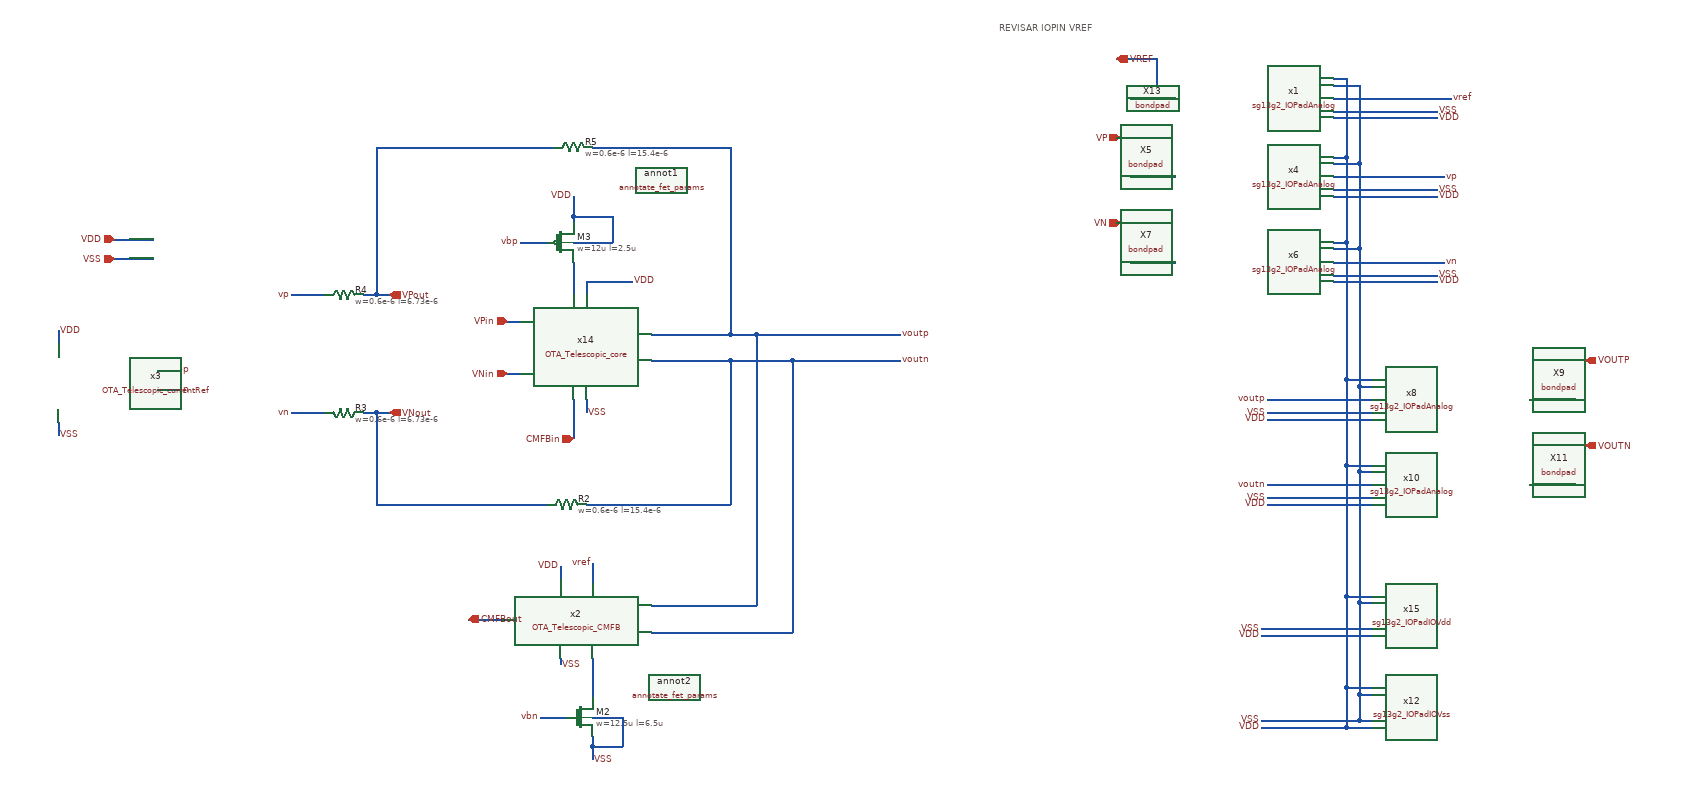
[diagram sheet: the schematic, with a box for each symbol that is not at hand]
v {xschem version=3.4.8RC file_version=1.3}
G {}
K {}
V {}
S {}
F {}
E {}
T {REVISAR IOPIN VREF} 1730 -1240 0 0 0.4 0.4 {}
N 1100 -660 1100 -640 {lab=VSS}
N 1080 -660 1080 -600 {lab=CMFBin}
N 1060 -265 1060 -255 {lab=VSS}
N 920 -325 970 -325 {lab=CMFBout}
N 1110 -1045 1320 -1045 {lab=voutp}
N 780 -640 780 -500 {lab=VNout}
N 1100 -500 1320 -500 {lab=voutp}
N 1320 -720 1320 -500 {lab=voutp}
N 1200 -305 1415 -305 {lab=voutp}
N 1200 -345 1360 -345 {lab=voutp}
N 1060 -405 1060 -385 {lab=VDD}
N 1110 -265 1110 -205 {lab=#net1}
N 780 -640 800 -640 {lab=VNout}
N 780 -820 800 -820 {lab=VPout}
N 1030 -175 1070 -175 {
lab=vbn}
N 1110 -175 1155 -175 {lab=VSS}
N 1155 -175 1155 -130 {lab=VSS}
N 1110 -130 1155 -130 {lab=VSS}
N 1110 -145 1110 -130 {lab=VSS}
N 1110 -130 1110 -110 {lab=VSS}
N 1080 -940 1080 -930 {lab=VDD}
N 1080 -900 1140 -900 {lab=VDD}
N 1140 -940 1140 -900 {lab=VDD}
N 1080 -940 1140 -940 {lab=VDD}
N 1080 -970 1080 -940 {lab=VDD}
N 445 -675 465 -675 {lab=vbn}
N 980 -700 1000 -700 {lab=VNin}
N 980 -780 1000 -780 {lab=VPin}
N 445 -705 465 -705 {lab=vbp}
N 1000 -900 1040 -900 {
lab=vbp}
N 780 -1045 780 -820 {lab=VPout}
N 1320 -1045 1320 -760 {lab=voutp}
N 1100 -840 1100 -820 {lab=VDD}
N 1100 -840 1170 -840 {lab=VDD}
N 1080 -870 1080 -820 {lab=#net2}
N 760 -640 780 -640 {lab=VNout}
N 780 -500 1040 -500 {lab=VNout}
N 760 -820 780 -820 {lab=VPout}
N 780 -1045 1050 -1045 {lab=VPout}
N 1200 -760 1320 -760 {lab=voutp}
N 1200 -720 1320 -720 {lab=voutp}
N 380 -905 440 -905 {lab=VDD}
N 380 -875 440 -875 {lab=VSS}
N 1360 -760 1360 -345 {lab=voutp}
N 1320 -760 1360 -760 {lab=voutp}
N 1415 -720 1415 -305 {lab=voutp}
N 295 -765 295 -745 {lab=VDD}
N 295 -625 295 -605 {lab=VSS}
N 1970 -1000 2000 -1000 {
lab=VP}
N 1910 -1060 1970 -1060 {
lab=VP}
N 1970 -1060 1970 -1000 {
lab=VP}
N 1930 -1000 1970 -1000 {
lab=VP}
N 650 -820 700 -820 {
lab=vp}
N 2240 -1000 2410 -1000 {
lab=vp}
N 1970 -870 2000 -870 {
lab=VN}
N 1910 -930 1970 -930 {
lab=VN}
N 1970 -930 1970 -870 {
lab=VN}
N 1930 -870 1970 -870 {
lab=VN}
N 2240 -870 2410 -870 {
lab=vn}
N 650 -640 700 -640 {
lab=vn}
N 2540 -660 2570 -660 {
lab=VOUTP}
N 2570 -720 2630 -720 {
lab=VOUTP}
N 2570 -720 2570 -660 {
lab=VOUTP}
N 2570 -660 2610 -660 {
lab=VOUTP}
N 2140 -660 2300 -660 {
lab=voutp}
N 2540 -530 2570 -530 {
lab=VOUTN}
N 2570 -590 2630 -590 {
lab=VOUTN}
N 2570 -590 2570 -530 {
lab=VOUTN}
N 2570 -530 2610 -530 {
lab=VOUTN}
N 2140 -530 2300 -530 {
lab=voutn}
N 1415 -720 1580 -720 {
lab=voutp}
N 1320 -720 1415 -720 {lab=voutp}
N 1360 -760 1580 -760 {
lab=voutp}
N 1970 -1120 2000 -1120 {
lab=VREF}
N 1910 -1180 1970 -1180 {
lab=VREF}
N 1970 -1180 1970 -1120 {
lab=VREF}
N 1930 -1120 1970 -1120 {
lab=VREF}
N 2240 -1120 2420 -1120 {
lab=vref}
N 1110 -410 1110 -380 {
lab=vref}
N 2280 -350 2300 -350 {
lab=VSS}
N 2280 -550 2300 -550 {
lab=VSS}
N 2280 -680 2300 -680 {
lab=VSS}
N 2140 -510 2300 -510 {
lab=VSS}
N 2140 -500 2300 -500 {
lab=VDD}
N 2140 -640 2300 -640 {
lab=VSS}
N 2140 -630 2300 -630 {
lab=VDD}
N 2240 -850 2400 -850 {
lab=VSS}
N 2240 -840 2400 -840 {
lab=VDD}
N 2240 -980 2400 -980 {
lab=VSS}
N 2240 -970 2400 -970 {
lab=VDD}
N 2240 -1100 2400 -1100 {
lab=VSS}
N 2240 -1090 2400 -1090 {
lab=VDD}
N 2240 -890 2280 -890 {
lab=VSS}
N 2240 -900 2260 -900 {
lab=VDD}
N 2240 -1020 2280 -1020 {
lab=VSS}
N 2240 -1030 2260 -1030 {
lab=VDD}
N 2240 -1140 2280 -1140 {
lab=VSS}
N 2240 -1150 2260 -1150 {
lab=VDD}
N 2260 -360 2300 -360 {
lab=VDD}
N 2130 -310 2300 -310 {
lab=VSS}
N 2130 -300 2300 -300 {
lab=VDD}
N 2280 -550 2280 -350 {
lab=VSS}
N 2260 -560 2300 -560 {
lab=VDD}
N 2260 -560 2260 -360 {
lab=VDD}
N 2260 -690 2260 -560 {
lab=VDD}
N 2260 -690 2300 -690 {
lab=VDD}
N 2280 -680 2280 -550 {
lab=VSS}
N 2260 -900 2260 -690 {
lab=VDD}
N 2280 -890 2280 -680 {
lab=VSS}
N 2280 -1020 2280 -890 {
lab=VSS}
N 2280 -1140 2280 -1020 {
lab=VSS}
N 2260 -1030 2260 -900 {
lab=VDD}
N 2260 -1150 2260 -1030 {
lab=VDD}
N 2260 -220 2260 -160 {lab=VDD}
N 2280 -170 2300 -170 {
lab=VSS}
N 2280 -210 2280 -170 {lab=VSS}
N 2260 -160 2300 -160 {
lab=VDD}
N 2130 -160 2260 -160 {
lab=VDD}
N 2130 -170 2280 -170 {
lab=VSS}
N 2280 -210 2300 -210 {lab=VSS}
N 2280 -350 2280 -210 {lab=VSS}
N 2260 -220 2300 -220 {lab=VDD}
N 2260 -360 2260 -220 {lab=VDD}
C {lab_wire.sym} 1170 -840 2 0 {name=p10 sig_type=std_logic lab=VDD}
C {OTA_Telescopic_CMFB.sym} 1120 -325 0 1 {name=x2}
C {sg13g2_pr/sg13_lv_pmos.sym} 1060 -900 0 0 {name=M3
l=2.5u
w=12u
ng=2
m=1
model=sg13_lv_pmos
spiceprefix=X
}
C {lab_wire.sym} 1080 -970 0 0 {name=p15 sig_type=std_logic lab=VDD}
C {lab_wire.sym} 295 -765 0 1 {name=p2 sig_type=std_logic lab=VDD}
C {sg13g2_pr/sg13_lv_nmos.sym} 1090 -175 0 0 {name=M2
l=6.5u
w=12.5u
ng=2
m=1
model=sg13_lv_nmos
spiceprefix=X
}
C {lab_wire.sym} 1030 -175 0 0 {name=p13 sig_type=std_logic lab=vbn}
C {lab_wire.sym} 465 -675 0 1 {name=p16 sig_type=std_logic lab=vbn}
C {lab_wire.sym} 1100 -640 2 0 {name=p1 sig_type=std_logic lab=VSS}
C {lab_wire.sym} 1060 -255 2 0 {name=p4 sig_type=std_logic lab=VSS}
C {lab_wire.sym} 1110 -110 2 0 {name=p17 sig_type=std_logic lab=VSS}
C {lab_wire.sym} 295 -605 2 0 {name=p20 sig_type=std_logic lab=VSS}
C {ipin.sym} 980 -780 0 0 {name=p6 lab=VPin}
C {ipin.sym} 980 -700 0 0 {name=p9 lab=VNin}
C {iopin.sym} 380 -905 2 0 {name=p19 lab=VDD}
C {iopin.sym} 380 -875 2 0 {name=p23 lab=VSS}
C {lab_wire.sym} 465 -705 0 1 {name=p24 sig_type=std_logic lab=vbp}
C {lab_wire.sym} 1000 -900 0 0 {name=p25 sig_type=std_logic lab=vbp}
C {ipin.sym} 1080 -600 0 0 {name=p3 lab=CMFBin}
C {opin.sym} 920 -325 2 0 {name=p14 lab=CMFBout}
C {sg13g2_pr/rppd.sym} 730 -640 1 0 {name=R3
w=0.6e-6
l=6.73e-6
model=rppd
body=VSS
spiceprefix=X
b=0
m=1
}
C {sg13g2_pr/rppd.sym} 730 -820 3 0 {name=R4
w=0.6e-6
l=6.73e-6
model=rppd
body=VSS
spiceprefix=X
b=0
m=1
}
C {sg13g2_pr/rppd.sym} 1080 -1045 3 0 {name=R5
w=0.6e-6
l=15.4e-6
model=rppd
body=VSS
spiceprefix=X
b=0
m=1
}
C {sg13g2_pr/rppd.sym} 1070 -500 3 0 {name=R2
w=0.6e-6
l=15.4e-6
model=rppd
body=VSS
spiceprefix=X
b=0
m=1
}
C {OTA_Telescopic_currentRef.sym} 295 -685 0 0 {name=x3}
C {sg13g2_pr/annotate_fet_params.sym} 1215 -995 0 0 {name=annot1 ref=M3}
C {sg13g2_pr/annotate_fet_params.sym} 1235 -220 0 0 {name=annot2 ref=M2}
C {ipin.sym} 1915 -1060 0 0 {name=p26 lab=VP}
C {sg13g2_pr/bondpad.sym} 1890 -1000 3 0 {name=X5
model=bondpad
spiceprefix=X
size=80u
shape=0
padtype=0
}
C {lab_wire.sym} 650 -820 0 0 {name=p27 sig_type=std_logic lab=vp}
C {lab_wire.sym} 2410 -1000 0 1 {name=p28 sig_type=std_logic lab=vp}
C {ipin.sym} 1915 -930 0 0 {name=p21 lab=VN}
C {sg13g2_pr/bondpad.sym} 1890 -870 3 0 {name=X7
model=bondpad
spiceprefix=X
size=80u
shape=0
padtype=0
}
C {lab_wire.sym} 2410 -870 0 1 {name=p29 sig_type=std_logic lab=vn}
C {lab_wire.sym} 650 -640 0 0 {name=p7 sig_type=std_logic lab=vn}
C {sg13g2_pr/bondpad.sym} 2650 -660 1 1 {name=X9
model=bondpad
spiceprefix=X
size=80u
shape=0
padtype=0
}
C {lab_wire.sym} 2140 -660 0 0 {name=p31 sig_type=std_logic lab=voutp}
C {sg13g2_pr/bondpad.sym} 2650 -530 1 1 {name=X11
model=bondpad
spiceprefix=X
size=80u
shape=0
padtype=0
}
C {opin.sym} 2625 -720 0 0 {name=p8 lab=VOUTP}
C {opin.sym} 2625 -590 0 0 {name=p22 lab=VOUTN}
C {lab_wire.sym} 1580 -720 0 1 {name=p30 sig_type=std_logic lab=voutn}
C {lab_wire.sym} 1580 -760 0 1 {name=p33 sig_type=std_logic lab=voutp}
C {lab_wire.sym} 2140 -530 0 0 {name=p37 sig_type=std_logic lab=voutn}
C {opin.sym} 800 -820 0 0 {name=p12 lab=VPout}
C {opin.sym} 800 -640 0 0 {name=p18 lab=VNout}
C {sg13g2_pr/bondpad.sym} 1890 -1120 3 0 {name=X13
model=bondpad
spiceprefix=X
size=80u
shape=0
padtype=0
}
C {lab_wire.sym} 2420 -1120 0 1 {name=p34 sig_type=std_logic lab=vref}
C {lab_wire.sym} 1110 -410 0 0 {name=p11 sig_type=std_logic lab=vref}
C {lab_wire.sym} 1060 -405 0 0 {name=p5 sig_type=std_logic lab=VDD}
C {OTA_Telescopic_core.sym} 1080 -740 0 0 {name=x14}
C {IOCells/sg13g2_IOPadAnalog.sym} 2120 -1120 0 1 {name=x1}
C {IOCells/sg13g2_IOPadAnalog.sym} 2120 -1000 0 1 {name=x4}
C {IOCells/sg13g2_IOPadAnalog.sym} 2120 -870 0 1 {name=x6}
C {IOCells/sg13g2_IOPadAnalog.sym} 2420 -660 0 0 {name=x8}
C {IOCells/sg13g2_IOPadAnalog.sym} 2420 -530 0 0 {name=x10}
C {lab_wire.sym} 2130 -310 0 0 {name=p42 sig_type=std_logic lab=VSS}
C {lab_wire.sym} 2130 -300 2 1 {name=p43 sig_type=std_logic lab=VDD}
C {lab_wire.sym} 2140 -510 0 0 {name=p48 sig_type=std_logic lab=VSS}
C {lab_wire.sym} 2140 -500 2 1 {name=p49 sig_type=std_logic lab=VDD}
C {lab_wire.sym} 2140 -640 0 0 {name=p50 sig_type=std_logic lab=VSS}
C {lab_wire.sym} 2140 -630 2 1 {name=p51 sig_type=std_logic lab=VDD}
C {lab_wire.sym} 2400 -850 0 1 {name=p52 sig_type=std_logic lab=VSS}
C {lab_wire.sym} 2400 -840 2 0 {name=p53 sig_type=std_logic lab=VDD}
C {lab_wire.sym} 2400 -980 0 1 {name=p54 sig_type=std_logic lab=VSS}
C {lab_wire.sym} 2400 -970 2 0 {name=p55 sig_type=std_logic lab=VDD}
C {lab_wire.sym} 2400 -1100 0 1 {name=p56 sig_type=std_logic lab=VSS}
C {lab_wire.sym} 2400 -1090 2 0 {name=p57 sig_type=std_logic lab=VDD}
C {sg13g2_IOPadIOVdd.sym} 2420 -330 0 0 {name=x15}
C {sg13g2_IOPadIOVss.sym} 2420 -190 0 0 {name=x12}
C {lab_wire.sym} 2130 -170 0 0 {name=p32 sig_type=std_logic lab=VSS}
C {lab_wire.sym} 2130 -160 2 1 {name=p36 sig_type=std_logic lab=VDD}
C {iopin.sym} 1910 -1180 0 1 {name=p35 lab=VREF}
